VERSION 5.7 ;
  NOWIREEXTENSIONATPIN ON ;
  DIVIDERCHAR "/" ;
  BUSBITCHARS "[]" ;
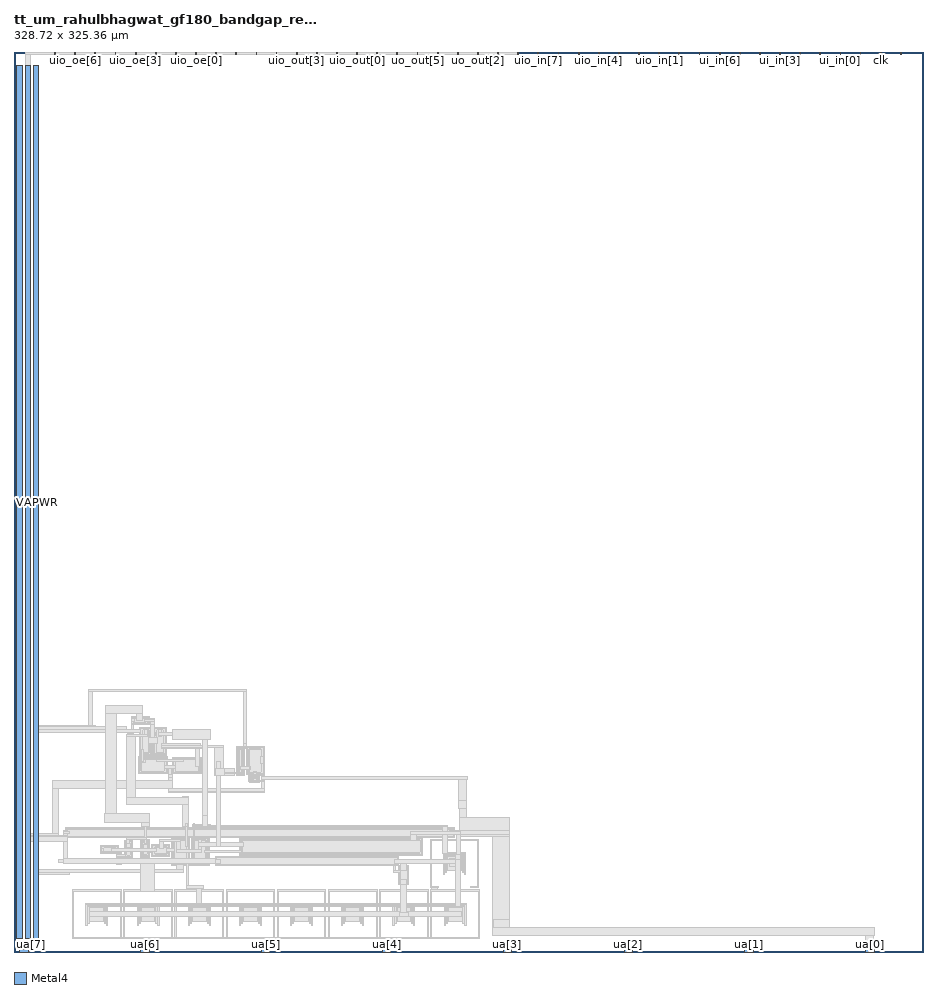
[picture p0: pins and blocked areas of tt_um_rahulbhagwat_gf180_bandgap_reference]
MACRO tt_um_rahulbhagwat_gf180_bandgap_reference
  CLASS BLOCK ;
  FOREIGN tt_um_rahulbhagwat_gf180_bandgap_reference ;
  ORIGIN 0.000 0.000 ;
  SIZE 328.720 BY 325.360 ;
  PIN clk
    DIRECTION INPUT ;
    USE SIGNAL ;
    PORT
      LAYER Metal4 ;
        RECT 313.170 324.360 313.470 325.360 ;
    END
  END clk
  PIN ena
    DIRECTION INPUT ;
    USE SIGNAL ;
    PORT
      LAYER Metal4 ;
        RECT 320.450 324.360 320.750 325.360 ;
    END
  END ena
  PIN rst_n
    DIRECTION INPUT ;
    USE SIGNAL ;
    PORT
      LAYER Metal4 ;
        RECT 305.890 324.360 306.190 325.360 ;
    END
  END rst_n
  PIN ua[0]
    DIRECTION INOUT ;
    USE SIGNAL ;
    ANTENNAGATEAREA 416.160004 ;
    ANTENNADIFFAREA 119.787193 ;
    PORT
      LAYER Metal4 ;
        RECT 307.900 0.000 310.900 1.000 ;
    END
  END ua[0]
  PIN ua[1]
    DIRECTION INOUT ;
    USE SIGNAL ;
    PORT
      LAYER Metal4 ;
        RECT 264.220 0.000 267.220 1.000 ;
    END
  END ua[1]
  PIN ua[2]
    DIRECTION INOUT ;
    USE SIGNAL ;
    PORT
      LAYER Metal4 ;
        RECT 220.540 0.000 223.540 1.000 ;
    END
  END ua[2]
  PIN ua[3]
    DIRECTION INOUT ;
    USE SIGNAL ;
    PORT
      LAYER Metal4 ;
        RECT 176.860 0.000 179.860 1.000 ;
    END
  END ua[3]
  PIN ua[4]
    DIRECTION INOUT ;
    USE SIGNAL ;
    PORT
      LAYER Metal4 ;
        RECT 133.180 0.000 136.180 1.000 ;
    END
  END ua[4]
  PIN ua[5]
    DIRECTION INOUT ;
    USE SIGNAL ;
    PORT
      LAYER Metal4 ;
        RECT 89.500 0.000 92.500 1.000 ;
    END
  END ua[5]
  PIN ua[6]
    DIRECTION INOUT ;
    USE SIGNAL ;
    PORT
      LAYER Metal4 ;
        RECT 45.820 0.000 48.820 1.000 ;
    END
  END ua[6]
  PIN ua[7]
    DIRECTION INOUT ;
    USE SIGNAL ;
    PORT
      LAYER Metal4 ;
        RECT 2.140 0.000 5.140 1.000 ;
    END
  END ua[7]
  PIN ui_in[0]
    DIRECTION INPUT ;
    USE SIGNAL ;
    PORT
      LAYER Metal4 ;
        RECT 298.610 324.360 298.910 325.360 ;
    END
  END ui_in[0]
  PIN ui_in[1]
    DIRECTION INPUT ;
    USE SIGNAL ;
    PORT
      LAYER Metal4 ;
        RECT 291.330 324.360 291.630 325.360 ;
    END
  END ui_in[1]
  PIN ui_in[2]
    DIRECTION INPUT ;
    USE SIGNAL ;
    PORT
      LAYER Metal4 ;
        RECT 284.050 324.360 284.350 325.360 ;
    END
  END ui_in[2]
  PIN ui_in[3]
    DIRECTION INPUT ;
    USE SIGNAL ;
    PORT
      LAYER Metal4 ;
        RECT 276.770 324.360 277.070 325.360 ;
    END
  END ui_in[3]
  PIN ui_in[4]
    DIRECTION INPUT ;
    USE SIGNAL ;
    PORT
      LAYER Metal4 ;
        RECT 269.490 324.360 269.790 325.360 ;
    END
  END ui_in[4]
  PIN ui_in[5]
    DIRECTION INPUT ;
    USE SIGNAL ;
    PORT
      LAYER Metal4 ;
        RECT 262.210 324.360 262.510 325.360 ;
    END
  END ui_in[5]
  PIN ui_in[6]
    DIRECTION INPUT ;
    USE SIGNAL ;
    PORT
      LAYER Metal4 ;
        RECT 254.930 324.360 255.230 325.360 ;
    END
  END ui_in[6]
  PIN ui_in[7]
    DIRECTION INPUT ;
    USE SIGNAL ;
    PORT
      LAYER Metal4 ;
        RECT 247.650 324.360 247.950 325.360 ;
    END
  END ui_in[7]
  PIN uio_in[0]
    DIRECTION INPUT ;
    USE SIGNAL ;
    PORT
      LAYER Metal4 ;
        RECT 240.370 324.360 240.670 325.360 ;
    END
  END uio_in[0]
  PIN uio_in[1]
    DIRECTION INPUT ;
    USE SIGNAL ;
    PORT
      LAYER Metal4 ;
        RECT 233.090 324.360 233.390 325.360 ;
    END
  END uio_in[1]
  PIN uio_in[2]
    DIRECTION INPUT ;
    USE SIGNAL ;
    PORT
      LAYER Metal4 ;
        RECT 225.810 324.360 226.110 325.360 ;
    END
  END uio_in[2]
  PIN uio_in[3]
    DIRECTION INPUT ;
    USE SIGNAL ;
    PORT
      LAYER Metal4 ;
        RECT 218.530 324.360 218.830 325.360 ;
    END
  END uio_in[3]
  PIN uio_in[4]
    DIRECTION INPUT ;
    USE SIGNAL ;
    PORT
      LAYER Metal4 ;
        RECT 211.250 324.360 211.550 325.360 ;
    END
  END uio_in[4]
  PIN uio_in[5]
    DIRECTION INPUT ;
    USE SIGNAL ;
    PORT
      LAYER Metal4 ;
        RECT 203.970 324.360 204.270 325.360 ;
    END
  END uio_in[5]
  PIN uio_in[6]
    DIRECTION INPUT ;
    USE SIGNAL ;
    PORT
      LAYER Metal4 ;
        RECT 196.690 324.360 196.990 325.360 ;
    END
  END uio_in[6]
  PIN uio_in[7]
    DIRECTION INPUT ;
    USE SIGNAL ;
    PORT
      LAYER Metal4 ;
        RECT 189.410 324.360 189.710 325.360 ;
    END
  END uio_in[7]
  PIN uio_oe[0]
    DIRECTION OUTPUT ;
    USE SIGNAL ;
    ANTENNADIFFAREA 455.790802 ;
    PORT
      LAYER Metal4 ;
        RECT 65.650 324.360 65.950 325.360 ;
    END
  END uio_oe[0]
  PIN uio_oe[1]
    DIRECTION OUTPUT ;
    USE SIGNAL ;
    ANTENNADIFFAREA 455.790802 ;
    PORT
      LAYER Metal4 ;
        RECT 58.370 324.360 58.670 325.360 ;
    END
  END uio_oe[1]
  PIN uio_oe[2]
    DIRECTION OUTPUT ;
    USE SIGNAL ;
    ANTENNADIFFAREA 455.790802 ;
    PORT
      LAYER Metal4 ;
        RECT 51.090 324.360 51.390 325.360 ;
    END
  END uio_oe[2]
  PIN uio_oe[3]
    DIRECTION OUTPUT ;
    USE SIGNAL ;
    ANTENNADIFFAREA 455.790802 ;
    PORT
      LAYER Metal4 ;
        RECT 43.810 324.360 44.110 325.360 ;
    END
  END uio_oe[3]
  PIN uio_oe[4]
    DIRECTION OUTPUT ;
    USE SIGNAL ;
    ANTENNADIFFAREA 455.790802 ;
    PORT
      LAYER Metal4 ;
        RECT 36.530 324.360 36.830 325.360 ;
    END
  END uio_oe[4]
  PIN uio_oe[5]
    DIRECTION OUTPUT ;
    USE SIGNAL ;
    ANTENNADIFFAREA 455.790802 ;
    PORT
      LAYER Metal4 ;
        RECT 29.250 324.360 29.550 325.360 ;
    END
  END uio_oe[5]
  PIN uio_oe[6]
    DIRECTION OUTPUT ;
    USE SIGNAL ;
    ANTENNADIFFAREA 455.790802 ;
    PORT
      LAYER Metal4 ;
        RECT 21.970 324.360 22.270 325.360 ;
    END
  END uio_oe[6]
  PIN uio_oe[7]
    DIRECTION OUTPUT ;
    USE SIGNAL ;
    ANTENNADIFFAREA 455.790802 ;
    PORT
      LAYER Metal4 ;
        RECT 14.690 324.360 14.990 325.360 ;
    END
  END uio_oe[7]
  PIN uio_out[0]
    DIRECTION OUTPUT ;
    USE SIGNAL ;
    ANTENNADIFFAREA 455.790802 ;
    PORT
      LAYER Metal4 ;
        RECT 123.890 324.360 124.190 325.360 ;
    END
  END uio_out[0]
  PIN uio_out[1]
    DIRECTION OUTPUT ;
    USE SIGNAL ;
    ANTENNADIFFAREA 455.790802 ;
    PORT
      LAYER Metal4 ;
        RECT 116.610 324.360 116.910 325.360 ;
    END
  END uio_out[1]
  PIN uio_out[2]
    DIRECTION OUTPUT ;
    USE SIGNAL ;
    ANTENNADIFFAREA 455.790802 ;
    PORT
      LAYER Metal4 ;
        RECT 109.330 324.360 109.630 325.360 ;
    END
  END uio_out[2]
  PIN uio_out[3]
    DIRECTION OUTPUT ;
    USE SIGNAL ;
    ANTENNADIFFAREA 455.790802 ;
    PORT
      LAYER Metal4 ;
        RECT 102.050 324.360 102.350 325.360 ;
    END
  END uio_out[3]
  PIN uio_out[4]
    DIRECTION OUTPUT ;
    USE SIGNAL ;
    ANTENNADIFFAREA 455.790802 ;
    PORT
      LAYER Metal4 ;
        RECT 94.770 324.360 95.070 325.360 ;
    END
  END uio_out[4]
  PIN uio_out[5]
    DIRECTION OUTPUT ;
    USE SIGNAL ;
    ANTENNADIFFAREA 455.790802 ;
    PORT
      LAYER Metal4 ;
        RECT 87.490 324.360 87.790 325.360 ;
    END
  END uio_out[5]
  PIN uio_out[6]
    DIRECTION OUTPUT ;
    USE SIGNAL ;
    ANTENNADIFFAREA 455.790802 ;
    PORT
      LAYER Metal4 ;
        RECT 80.210 324.360 80.510 325.360 ;
    END
  END uio_out[6]
  PIN uio_out[7]
    DIRECTION OUTPUT ;
    USE SIGNAL ;
    ANTENNADIFFAREA 455.790802 ;
    PORT
      LAYER Metal4 ;
        RECT 72.930 324.360 73.230 325.360 ;
    END
  END uio_out[7]
  PIN uo_out[0]
    DIRECTION OUTPUT ;
    USE SIGNAL ;
    ANTENNADIFFAREA 455.790802 ;
    PORT
      LAYER Metal4 ;
        RECT 182.130 324.360 182.430 325.360 ;
    END
  END uo_out[0]
  PIN uo_out[1]
    DIRECTION OUTPUT ;
    USE SIGNAL ;
    ANTENNADIFFAREA 455.790802 ;
    PORT
      LAYER Metal4 ;
        RECT 174.850 324.360 175.150 325.360 ;
    END
  END uo_out[1]
  PIN uo_out[2]
    DIRECTION OUTPUT ;
    USE SIGNAL ;
    ANTENNADIFFAREA 455.790802 ;
    PORT
      LAYER Metal4 ;
        RECT 167.570 324.360 167.870 325.360 ;
    END
  END uo_out[2]
  PIN uo_out[3]
    DIRECTION OUTPUT ;
    USE SIGNAL ;
    ANTENNADIFFAREA 455.790802 ;
    PORT
      LAYER Metal4 ;
        RECT 160.290 324.360 160.590 325.360 ;
    END
  END uo_out[3]
  PIN uo_out[4]
    DIRECTION OUTPUT ;
    USE SIGNAL ;
    ANTENNADIFFAREA 455.790802 ;
    PORT
      LAYER Metal4 ;
        RECT 153.010 324.360 153.310 325.360 ;
    END
  END uo_out[4]
  PIN uo_out[5]
    DIRECTION OUTPUT ;
    USE SIGNAL ;
    ANTENNADIFFAREA 455.790802 ;
    PORT
      LAYER Metal4 ;
        RECT 145.730 324.360 146.030 325.360 ;
    END
  END uo_out[5]
  PIN uo_out[6]
    DIRECTION OUTPUT ;
    USE SIGNAL ;
    ANTENNADIFFAREA 455.790802 ;
    PORT
      LAYER Metal4 ;
        RECT 138.450 324.360 138.750 325.360 ;
    END
  END uo_out[6]
  PIN uo_out[7]
    DIRECTION OUTPUT ;
    USE SIGNAL ;
    ANTENNADIFFAREA 455.790802 ;
    PORT
      LAYER Metal4 ;
        RECT 131.170 324.360 131.470 325.360 ;
    END
  END uo_out[7]
  PIN VDPWR
    DIRECTION INOUT ;
    USE POWER ;
    PORT
      LAYER Metal4 ;
        RECT 1.000 5.000 3.000 320.360 ;
    END
  END VDPWR
  PIN VGND
    DIRECTION INOUT ;
    USE GROUND ;
    PORT
      LAYER Metal4 ;
        RECT 4.000 5.000 6.000 320.360 ;
    END
  END VGND
  PIN VAPWR
    DIRECTION INOUT ;
    USE POWER ;
    PORT
      LAYER Metal4 ;
        RECT 7.000 5.000 9.000 320.360 ;
    END
  END VAPWR
  OBS
      LAYER Nwell ;
        RECT 42.350 82.205 48.850 85.305 ;
        RECT 45.400 71.155 49.900 81.255 ;
        RECT 50.550 71.205 55.050 81.305 ;
      LAYER Pwell ;
        RECT 44.950 64.405 55.450 70.505 ;
        RECT 57.410 64.370 67.910 70.470 ;
      LAYER Nwell ;
        RECT 80.600 63.850 83.200 74.350 ;
        RECT 83.950 64.150 90.450 74.250 ;
      LAYER Pwell ;
        RECT 85.300 61.250 88.840 63.650 ;
        RECT 18.750 41.500 159.330 44.860 ;
        RECT 31.300 35.450 37.800 38.550 ;
        RECT 39.800 33.950 42.900 40.450 ;
      LAYER Nwell ;
        RECT 45.900 34.300 49.000 40.800 ;
        RECT 49.750 34.650 56.250 38.750 ;
        RECT 56.900 31.150 63.400 41.250 ;
        RECT 64.000 31.200 70.500 41.300 ;
        RECT 81.650 34.900 147.750 41.400 ;
      LAYER Pwell ;
        RECT 72.900 31.100 139.130 34.460 ;
        RECT 139.150 24.550 142.690 31.130 ;
      LAYER Metal1 ;
        RECT 26.950 94.000 84.150 95.000 ;
        RECT 26.950 82.000 28.300 94.000 ;
        RECT 44.445 87.280 45.445 88.280 ;
        RECT 42.535 84.890 48.665 85.120 ;
        RECT 42.535 84.305 42.765 84.890 ;
        RECT 43.610 84.420 47.590 84.650 ;
        RECT 42.535 84.245 43.300 84.305 ;
        RECT 42.535 83.265 43.455 84.245 ;
        RECT 44.440 83.715 46.420 84.420 ;
        RECT 47.745 84.140 47.975 84.245 ;
        RECT 47.115 83.350 47.975 84.140 ;
        RECT 47.745 83.265 47.975 83.350 ;
        RECT 42.535 83.255 43.300 83.265 ;
        RECT 42.535 82.620 43.050 83.255 ;
        RECT 43.610 82.860 47.590 83.090 ;
        RECT 48.435 82.620 48.665 84.890 ;
        RECT 42.535 82.390 48.665 82.620 ;
        RECT 6.950 81.500 29.350 82.000 ;
        RECT 6.950 80.405 40.800 81.500 ;
        RECT 42.550 80.405 43.050 82.390 ;
        RECT 45.585 80.840 49.715 81.070 ;
        RECT 45.585 80.405 45.815 80.840 ;
        RECT 6.950 79.405 45.850 80.405 ;
        RECT 46.660 80.370 48.640 80.600 ;
        RECT 6.950 79.350 40.800 79.405 ;
        RECT 26.950 79.300 40.800 79.350 ;
        RECT 26.950 79.250 28.300 79.300 ;
        RECT 41.140 76.595 42.740 79.095 ;
        RECT 45.585 71.570 45.815 79.405 ;
        RECT 46.275 73.265 46.505 80.195 ;
        RECT 47.215 77.895 48.180 80.370 ;
        RECT 48.795 77.405 49.025 80.195 ;
        RECT 49.485 79.405 49.715 80.840 ;
        RECT 50.735 80.890 54.865 81.120 ;
        RECT 50.735 79.405 50.965 80.890 ;
        RECT 51.810 80.420 53.790 80.650 ;
        RECT 49.450 78.405 51.000 79.405 ;
        RECT 48.450 75.405 49.050 77.405 ;
        RECT 46.045 72.410 46.750 73.265 ;
        RECT 46.275 72.215 46.505 72.410 ;
        RECT 48.795 72.215 49.025 75.405 ;
        RECT 46.660 71.810 48.640 72.040 ;
        RECT 49.485 71.570 49.715 78.405 ;
        RECT 45.585 71.340 49.715 71.570 ;
        RECT 50.735 71.620 50.965 78.405 ;
        RECT 51.425 77.405 51.655 80.245 ;
        RECT 52.285 77.975 53.410 80.420 ;
        RECT 51.400 75.405 51.850 77.405 ;
        RECT 51.425 72.265 51.655 75.405 ;
        RECT 53.945 75.400 54.175 80.245 ;
        RECT 53.435 73.760 54.180 75.400 ;
        RECT 53.945 72.265 54.175 73.760 ;
        RECT 51.810 71.860 53.790 72.090 ;
        RECT 54.635 71.620 54.865 80.890 ;
        RECT 57.715 77.440 60.315 79.940 ;
        RECT 82.900 75.250 84.150 94.000 ;
        RECT 68.485 73.725 69.485 74.725 ;
        RECT 82.900 74.165 83.900 75.250 ;
        RECT 80.785 74.150 83.900 74.165 ;
        RECT 80.785 74.065 84.350 74.150 ;
        RECT 80.785 73.935 90.265 74.065 ;
        RECT 50.735 71.390 54.865 71.620 ;
        RECT 45.135 70.090 55.265 70.320 ;
        RECT 45.135 64.820 45.365 70.090 ;
        RECT 51.450 69.850 53.410 69.855 ;
        RECT 46.210 69.845 54.190 69.850 ;
        RECT 45.800 69.620 54.190 69.845 ;
        RECT 45.800 68.400 47.450 69.620 ;
        RECT 51.450 68.905 53.410 69.620 ;
        RECT 45.825 65.465 46.055 68.400 ;
        RECT 54.345 67.390 54.575 69.445 ;
        RECT 55.035 67.390 55.265 70.090 ;
        RECT 57.595 70.055 67.725 70.285 ;
        RECT 57.595 67.390 57.825 70.055 ;
        RECT 58.670 69.585 66.650 69.815 ;
        RECT 58.285 67.390 58.515 69.410 ;
        RECT 59.455 68.935 61.445 69.585 ;
        RECT 66.805 68.685 67.035 69.410 ;
        RECT 54.325 66.395 58.525 67.390 ;
        RECT 65.920 67.275 67.070 68.685 ;
        RECT 54.345 65.465 54.575 66.395 ;
        RECT 46.210 65.060 54.190 65.290 ;
        RECT 55.035 64.820 55.265 66.395 ;
        RECT 45.135 64.590 55.265 64.820 ;
        RECT 55.775 64.100 57.015 66.395 ;
        RECT 57.595 64.785 57.825 66.395 ;
        RECT 58.285 65.430 58.515 66.395 ;
        RECT 66.805 65.430 67.035 67.275 ;
        RECT 58.670 65.025 66.650 65.255 ;
        RECT 67.495 64.785 67.725 70.055 ;
        RECT 57.595 64.555 67.725 64.785 ;
        RECT 78.000 65.000 79.000 65.200 ;
        RECT 78.000 64.500 79.700 65.000 ;
        RECT 78.000 64.200 79.000 64.500 ;
        RECT 80.785 64.265 81.015 73.935 ;
        RECT 81.400 73.835 90.265 73.935 ;
        RECT 81.400 73.650 84.365 73.835 ;
        RECT 81.400 73.350 82.450 73.650 ;
        RECT 81.660 73.245 82.140 73.350 ;
        RECT 81.255 65.110 81.485 73.090 ;
        RECT 82.315 66.900 82.545 73.090 ;
        RECT 82.000 66.000 82.550 66.900 ;
        RECT 82.315 65.110 82.545 66.000 ;
        RECT 81.660 64.850 82.140 64.955 ;
        RECT 81.350 64.500 82.350 64.850 ;
        RECT 82.785 64.265 83.015 73.650 ;
        RECT 84.135 64.565 84.365 73.650 ;
        RECT 85.210 73.365 89.190 73.595 ;
        RECT 84.825 67.050 85.055 73.190 ;
        RECT 89.345 70.650 89.575 73.190 ;
        RECT 90.035 70.650 90.265 73.835 ;
        RECT 89.250 68.150 90.265 70.650 ;
        RECT 84.750 65.850 85.600 67.050 ;
        RECT 84.825 65.210 85.055 65.850 ;
        RECT 89.345 65.210 89.575 68.150 ;
        RECT 86.550 65.035 87.550 65.200 ;
        RECT 85.210 64.805 89.190 65.035 ;
        RECT 86.550 64.800 87.550 64.805 ;
        RECT 90.035 64.565 90.265 68.150 ;
        RECT 84.135 64.335 90.265 64.565 ;
        RECT 55.750 63.250 57.200 64.100 ;
        RECT 80.785 64.035 83.015 64.265 ;
        RECT 14.000 61.900 30.000 62.050 ;
        RECT 13.950 61.850 30.000 61.900 ;
        RECT 55.700 61.850 57.400 63.250 ;
        RECT 13.950 59.000 57.400 61.850 ;
        RECT 85.485 63.235 88.655 63.465 ;
        RECT 85.485 61.665 85.715 63.235 ;
        RECT 85.950 62.565 86.350 62.950 ;
        RECT 86.580 62.765 87.560 62.995 ;
        RECT 86.855 62.670 87.405 62.765 ;
        RECT 88.425 62.700 88.655 63.235 ;
        RECT 87.900 62.565 88.700 62.700 ;
        RECT 85.950 62.335 86.460 62.565 ;
        RECT 87.680 62.335 88.700 62.565 ;
        RECT 89.395 62.390 90.395 63.390 ;
        RECT 85.950 61.950 86.350 62.335 ;
        RECT 87.900 62.150 88.700 62.335 ;
        RECT 86.580 61.905 87.560 62.135 ;
        RECT 87.900 62.100 90.450 62.150 ;
        RECT 88.350 61.665 90.450 62.100 ;
        RECT 85.485 61.550 90.450 61.665 ;
        RECT 85.485 61.435 88.655 61.550 ;
        RECT 13.950 43.000 15.950 59.000 ;
        RECT 28.000 58.950 57.400 59.000 ;
        RECT 89.400 58.950 90.450 61.550 ;
        RECT 55.700 58.000 90.700 58.950 ;
        RECT 55.900 57.800 90.700 58.000 ;
        RECT 73.500 47.250 74.500 48.250 ;
        RECT 46.950 45.550 47.950 46.550 ;
        RECT 61.900 45.350 62.900 46.350 ;
        RECT 64.500 45.100 65.500 46.100 ;
        RECT 18.935 44.445 159.145 44.675 ;
        RECT 18.935 43.750 19.165 44.445 ;
        RECT 17.900 43.650 19.500 43.750 ;
        RECT 19.995 43.650 20.225 43.670 ;
        RECT 4.000 41.950 16.000 43.000 ;
        RECT 17.900 42.700 20.225 43.650 ;
        RECT 157.600 42.700 158.150 43.700 ;
        RECT 17.900 41.950 19.500 42.700 ;
        RECT 19.995 42.690 20.225 42.700 ;
        RECT 157.855 42.690 158.085 42.700 ;
        RECT 4.000 41.915 19.500 41.950 ;
        RECT 158.915 41.915 159.145 44.445 ;
        RECT 161.900 42.900 163.650 43.850 ;
        RECT 4.000 41.685 159.145 41.915 ;
        RECT 4.000 40.000 19.500 41.685 ;
        RECT 57.085 40.835 63.215 41.065 ;
        RECT 46.085 40.385 48.815 40.615 ;
        RECT 13.950 39.950 15.950 40.000 ;
        RECT 17.900 33.500 19.500 40.000 ;
        RECT 39.985 40.035 42.715 40.265 ;
        RECT 31.485 38.135 37.615 38.365 ;
        RECT 31.485 37.500 31.715 38.135 ;
        RECT 35.250 37.895 36.100 37.900 ;
        RECT 32.560 37.665 36.540 37.895 ;
        RECT 31.485 37.490 32.350 37.500 ;
        RECT 31.485 36.510 32.405 37.490 ;
        RECT 31.485 36.500 32.350 36.510 ;
        RECT 31.485 35.865 31.715 36.500 ;
        RECT 35.250 36.335 36.100 37.665 ;
        RECT 36.695 37.350 36.925 37.490 ;
        RECT 36.550 36.750 36.950 37.350 ;
        RECT 36.695 36.510 36.925 36.750 ;
        RECT 32.560 36.105 36.540 36.335 ;
        RECT 35.250 36.100 36.100 36.105 ;
        RECT 37.385 35.865 37.615 38.135 ;
        RECT 31.485 35.850 37.615 35.865 ;
        RECT 31.485 35.635 38.900 35.850 ;
        RECT 36.950 35.350 38.900 35.635 ;
        RECT 39.985 35.350 40.215 40.035 ;
        RECT 40.950 39.575 41.800 39.800 ;
        RECT 40.860 39.345 41.840 39.575 ;
        RECT 36.950 35.300 40.215 35.350 ;
        RECT 16.100 32.500 19.500 33.500 ;
        RECT 17.900 31.850 19.500 32.500 ;
        RECT 37.000 34.365 40.215 35.300 ;
        RECT 40.455 37.800 40.685 39.190 ;
        RECT 42.015 37.800 42.245 39.190 ;
        RECT 40.455 36.350 42.245 37.800 ;
        RECT 40.455 35.210 40.685 36.350 ;
        RECT 42.015 35.210 42.245 36.350 ;
        RECT 40.860 34.825 41.840 35.055 ;
        RECT 40.900 34.365 41.800 34.825 ;
        RECT 42.485 34.365 42.715 40.035 ;
        RECT 46.085 34.715 46.315 40.385 ;
        RECT 46.960 39.800 47.940 39.925 ;
        RECT 46.750 39.540 48.200 39.800 ;
        RECT 46.555 38.950 48.345 39.540 ;
        RECT 46.555 35.560 46.785 38.950 ;
        RECT 48.115 35.560 48.345 38.950 ;
        RECT 48.585 37.400 48.815 40.385 ;
        RECT 49.935 38.335 56.065 38.565 ;
        RECT 49.935 37.400 50.165 38.335 ;
        RECT 51.010 37.865 54.990 38.095 ;
        RECT 48.585 35.850 50.200 37.400 ;
        RECT 50.625 37.300 50.855 37.690 ;
        RECT 52.900 37.450 53.900 37.865 ;
        RECT 55.145 37.300 55.375 37.690 ;
        RECT 55.835 37.300 56.065 38.335 ;
        RECT 57.085 37.300 57.315 40.835 ;
        RECT 59.050 40.595 60.150 40.600 ;
        RECT 58.160 40.365 62.140 40.595 ;
        RECT 57.775 37.300 58.005 40.190 ;
        RECT 59.050 40.100 60.150 40.365 ;
        RECT 62.295 39.300 62.525 40.190 ;
        RECT 62.150 38.300 62.600 39.300 ;
        RECT 50.625 36.300 51.400 37.300 ;
        RECT 55.145 36.300 58.005 37.300 ;
        RECT 46.960 35.175 47.940 35.405 ;
        RECT 47.050 34.715 47.850 35.175 ;
        RECT 48.585 34.715 48.815 35.850 ;
        RECT 49.935 35.065 50.165 35.850 ;
        RECT 50.625 35.710 50.855 36.300 ;
        RECT 55.145 35.710 55.375 36.300 ;
        RECT 51.010 35.305 54.990 35.535 ;
        RECT 55.835 35.065 56.065 36.300 ;
        RECT 49.935 34.835 56.065 35.065 ;
        RECT 46.085 34.485 48.815 34.715 ;
        RECT 37.000 34.200 42.715 34.365 ;
        RECT 37.000 31.850 38.900 34.200 ;
        RECT 39.985 34.135 42.715 34.200 ;
        RECT 57.085 31.565 57.315 36.300 ;
        RECT 57.775 32.210 58.005 36.300 ;
        RECT 62.295 33.650 62.525 38.300 ;
        RECT 62.295 32.350 62.750 33.650 ;
        RECT 62.295 32.210 62.525 32.350 ;
        RECT 62.985 32.150 63.215 40.835 ;
        RECT 64.185 40.885 70.315 41.115 ;
        RECT 64.185 32.150 64.415 40.885 ;
        RECT 65.260 40.415 69.240 40.645 ;
        RECT 66.850 40.250 67.950 40.415 ;
        RECT 64.875 39.300 65.105 40.240 ;
        RECT 64.800 38.300 65.250 39.300 ;
        RECT 64.875 32.260 65.105 38.300 ;
        RECT 69.395 36.750 69.625 40.240 ;
        RECT 70.085 36.750 70.315 40.885 ;
        RECT 81.835 40.985 147.565 41.215 ;
        RECT 81.835 36.750 82.065 40.985 ;
        RECT 143.400 40.525 145.350 40.650 ;
        RECT 82.710 40.295 146.690 40.525 ;
        RECT 143.400 40.250 145.350 40.295 ;
        RECT 82.305 39.300 82.535 40.140 ;
        RECT 82.300 38.300 82.700 39.300 ;
        RECT 68.900 35.800 82.065 36.750 ;
        RECT 82.305 36.160 82.535 38.300 ;
        RECT 146.865 36.160 147.095 40.140 ;
        RECT 69.395 32.260 69.625 35.800 ;
        RECT 58.160 31.805 62.140 32.035 ;
        RECT 62.985 31.615 64.415 32.150 ;
        RECT 65.260 31.855 69.240 32.085 ;
        RECT 70.085 31.615 70.315 35.800 ;
        RECT 81.835 35.315 82.065 35.800 ;
        RECT 82.710 35.775 146.690 36.005 ;
        RECT 143.600 35.315 145.250 35.775 ;
        RECT 147.335 35.315 147.565 40.985 ;
        RECT 81.835 35.085 147.565 35.315 ;
        RECT 150.400 40.420 168.040 40.840 ;
        RECT 73.085 34.045 138.945 34.275 ;
        RECT 73.085 33.450 73.315 34.045 ;
        RECT 73.050 32.150 74.450 33.450 ;
        RECT 137.400 32.300 137.950 33.300 ;
        RECT 137.655 32.290 137.885 32.300 ;
        RECT 62.985 31.565 70.315 31.615 ;
        RECT 57.085 31.400 70.315 31.565 ;
        RECT 57.085 31.335 63.215 31.400 ;
        RECT 64.185 31.385 70.315 31.400 ;
        RECT 73.085 31.515 73.315 32.150 ;
        RECT 138.715 31.515 138.945 34.045 ;
        RECT 58.850 30.300 61.400 31.335 ;
        RECT 73.085 31.285 138.945 31.515 ;
        RECT 17.900 28.750 18.900 29.750 ;
        RECT 137.350 29.300 137.900 31.285 ;
        RECT 139.335 30.715 142.505 30.945 ;
        RECT 139.335 29.300 139.565 30.715 ;
        RECT 140.350 29.885 141.500 29.900 ;
        RECT 140.340 29.655 141.500 29.885 ;
        RECT 140.350 29.500 141.500 29.655 ;
        RECT 137.350 28.800 139.600 29.300 ;
        RECT 139.335 24.965 139.565 28.800 ;
        RECT 140.350 26.025 141.500 26.200 ;
        RECT 140.340 25.795 141.500 26.025 ;
        RECT 142.275 24.965 142.505 30.715 ;
        RECT 139.335 24.735 142.505 24.965 ;
        RECT 150.400 23.620 150.820 40.420 ;
        RECT 155.250 36.000 156.500 36.550 ;
        RECT 155.240 35.580 163.200 36.000 ;
        RECT 155.240 28.040 155.660 35.580 ;
        RECT 155.980 34.840 162.460 35.260 ;
        RECT 155.980 28.780 156.400 34.840 ;
        RECT 156.720 29.520 161.720 34.520 ;
        RECT 162.040 28.780 162.460 34.840 ;
        RECT 162.780 28.040 163.200 35.580 ;
        RECT 167.620 23.620 168.040 40.420 ;
        RECT 150.400 23.200 153.320 23.620 ;
        RECT 165.120 23.600 168.040 23.620 ;
        RECT 165.120 23.200 168.050 23.600 ;
        RECT 150.900 22.440 152.950 23.200 ;
        RECT 21.150 22.020 38.790 22.440 ;
        RECT 21.150 5.220 21.570 22.020 ;
        RECT 25.990 17.180 33.950 17.600 ;
        RECT 25.990 9.640 26.410 17.180 ;
        RECT 26.730 16.440 33.210 16.860 ;
        RECT 26.730 10.380 27.150 16.440 ;
        RECT 27.470 11.120 32.470 16.120 ;
        RECT 32.790 10.380 33.210 16.440 ;
        RECT 33.530 9.640 33.950 17.180 ;
        RECT 38.370 5.220 38.790 22.020 ;
        RECT 21.150 5.200 24.070 5.220 ;
        RECT 35.870 5.200 38.790 5.220 ;
        RECT 39.650 22.020 57.290 22.440 ;
        RECT 39.650 5.220 40.070 22.020 ;
        RECT 44.490 17.180 52.450 17.600 ;
        RECT 44.490 9.640 44.910 17.180 ;
        RECT 45.230 16.440 51.710 16.860 ;
        RECT 45.230 10.380 45.650 16.440 ;
        RECT 45.970 11.120 50.970 16.120 ;
        RECT 51.290 10.380 51.710 16.440 ;
        RECT 52.030 9.640 52.450 17.180 ;
        RECT 56.870 5.220 57.290 22.020 ;
        RECT 39.650 5.200 42.570 5.220 ;
        RECT 54.370 5.200 57.290 5.220 ;
        RECT 58.150 22.020 75.790 22.440 ;
        RECT 58.150 5.220 58.570 22.020 ;
        RECT 62.990 17.180 70.950 17.600 ;
        RECT 62.990 9.640 63.410 17.180 ;
        RECT 63.730 16.440 70.210 16.860 ;
        RECT 63.730 10.380 64.150 16.440 ;
        RECT 64.470 11.120 69.470 16.120 ;
        RECT 69.790 10.380 70.210 16.440 ;
        RECT 70.530 9.640 70.950 17.180 ;
        RECT 75.370 5.220 75.790 22.020 ;
        RECT 58.150 5.200 61.070 5.220 ;
        RECT 72.870 5.200 75.790 5.220 ;
        RECT 76.650 22.020 94.290 22.440 ;
        RECT 76.650 5.220 77.070 22.020 ;
        RECT 81.490 17.180 89.450 17.600 ;
        RECT 81.490 9.640 81.910 17.180 ;
        RECT 82.230 16.440 88.710 16.860 ;
        RECT 82.230 10.380 82.650 16.440 ;
        RECT 82.970 11.120 87.970 16.120 ;
        RECT 88.290 10.380 88.710 16.440 ;
        RECT 89.030 9.640 89.450 17.180 ;
        RECT 93.870 5.220 94.290 22.020 ;
        RECT 76.650 5.200 79.570 5.220 ;
        RECT 91.370 5.200 94.290 5.220 ;
        RECT 95.150 22.020 112.790 22.440 ;
        RECT 95.150 5.220 95.570 22.020 ;
        RECT 99.990 17.180 107.950 17.600 ;
        RECT 99.990 9.640 100.410 17.180 ;
        RECT 100.730 16.440 107.210 16.860 ;
        RECT 100.730 10.380 101.150 16.440 ;
        RECT 101.470 11.120 106.470 16.120 ;
        RECT 106.790 10.380 107.210 16.440 ;
        RECT 107.530 9.640 107.950 17.180 ;
        RECT 112.370 5.220 112.790 22.020 ;
        RECT 95.150 5.200 98.070 5.220 ;
        RECT 109.870 5.200 112.790 5.220 ;
        RECT 113.650 22.020 131.290 22.440 ;
        RECT 113.650 5.220 114.070 22.020 ;
        RECT 118.490 17.180 126.450 17.600 ;
        RECT 118.490 9.640 118.910 17.180 ;
        RECT 119.230 16.440 125.710 16.860 ;
        RECT 119.230 10.380 119.650 16.440 ;
        RECT 119.970 11.120 124.970 16.120 ;
        RECT 125.290 10.380 125.710 16.440 ;
        RECT 126.030 9.640 126.450 17.180 ;
        RECT 130.870 5.220 131.290 22.020 ;
        RECT 113.650 5.200 116.570 5.220 ;
        RECT 128.370 5.200 131.290 5.220 ;
        RECT 132.150 22.020 149.790 22.440 ;
        RECT 132.150 5.220 132.570 22.020 ;
        RECT 136.990 17.180 144.950 17.600 ;
        RECT 136.990 9.640 137.410 17.180 ;
        RECT 137.730 16.440 144.210 16.860 ;
        RECT 137.730 10.380 138.150 16.440 ;
        RECT 138.470 11.120 143.470 16.120 ;
        RECT 143.790 10.380 144.210 16.440 ;
        RECT 144.530 9.640 144.950 17.180 ;
        RECT 149.370 5.220 149.790 22.020 ;
        RECT 132.150 5.200 135.070 5.220 ;
        RECT 146.870 5.200 149.790 5.220 ;
        RECT 150.650 22.020 168.290 22.440 ;
        RECT 150.650 5.220 151.070 22.020 ;
        RECT 155.490 17.180 163.450 17.600 ;
        RECT 155.490 9.640 155.910 17.180 ;
        RECT 156.230 16.440 162.710 16.860 ;
        RECT 156.230 10.380 156.650 16.440 ;
        RECT 156.970 11.120 161.970 16.120 ;
        RECT 162.290 10.380 162.710 16.440 ;
        RECT 163.030 9.640 163.450 17.180 ;
        RECT 167.870 5.220 168.290 22.020 ;
        RECT 150.650 5.200 153.570 5.220 ;
        RECT 165.370 5.200 168.290 5.220 ;
        RECT 21.150 4.800 168.300 5.200 ;
      LAYER Metal2 ;
        RECT 32.900 86.350 46.350 89.000 ;
        RECT 7.000 79.350 9.000 82.000 ;
        RECT 32.900 50.000 36.950 86.350 ;
        RECT 44.155 83.715 46.345 86.350 ;
        RECT 49.435 84.125 50.885 84.385 ;
        RECT 47.130 83.405 50.885 84.125 ;
        RECT 47.130 83.370 50.900 83.405 ;
        RECT 49.435 82.390 50.900 83.370 ;
        RECT 41.140 79.085 42.790 79.095 ;
        RECT 40.865 78.650 43.285 79.085 ;
        RECT 40.700 77.865 48.235 78.650 ;
        RECT 40.700 56.000 44.050 77.865 ;
        RECT 49.450 77.405 50.900 82.390 ;
        RECT 57.400 79.405 61.050 80.300 ;
        RECT 52.275 78.100 61.050 79.405 ;
        RECT 48.450 75.405 51.850 77.405 ;
        RECT 57.400 77.350 61.050 78.100 ;
        RECT 53.445 74.725 67.440 75.355 ;
        RECT 53.445 74.650 69.485 74.725 ;
        RECT 72.650 74.650 75.650 74.700 ;
        RECT 53.445 73.800 75.650 74.650 ;
        RECT 53.445 73.725 69.485 73.800 ;
        RECT 53.445 73.405 67.440 73.725 ;
        RECT 46.000 68.830 46.750 73.275 ;
        RECT 51.460 68.945 61.435 69.770 ;
        RECT 65.455 67.230 67.070 73.405 ;
        RECT 72.650 66.200 75.650 73.800 ;
        RECT 72.500 65.000 79.550 66.200 ;
        RECT 82.000 65.900 85.250 67.150 ;
        RECT 72.500 64.500 82.350 65.000 ;
        RECT 72.500 63.800 79.550 64.500 ;
        RECT 84.750 62.500 85.250 65.900 ;
        RECT 86.550 64.850 87.550 65.300 ;
        RECT 86.600 64.800 87.500 64.850 ;
        RECT 86.650 64.100 87.500 64.800 ;
        RECT 86.650 64.095 88.100 64.100 ;
        RECT 86.650 64.080 90.185 64.095 ;
        RECT 86.650 63.645 90.395 64.080 ;
        RECT 86.650 63.600 87.850 63.645 ;
        RECT 86.650 62.960 87.500 63.600 ;
        RECT 89.390 63.550 90.395 63.645 ;
        RECT 89.390 63.500 96.850 63.550 ;
        RECT 86.650 62.650 87.550 62.960 ;
        RECT 84.750 61.950 86.350 62.500 ;
        RECT 89.390 62.370 164.000 63.500 ;
        RECT 89.400 62.350 164.000 62.370 ;
        RECT 94.550 62.200 164.000 62.350 ;
        RECT 84.750 61.750 85.250 61.950 ;
        RECT 61.000 56.000 63.050 56.050 ;
        RECT 40.700 53.150 63.050 56.000 ;
        RECT 32.750 46.850 49.150 50.000 ;
        RECT 46.050 45.450 49.000 46.850 ;
        RECT 46.950 45.300 47.950 45.450 ;
        RECT 61.000 45.350 63.050 53.150 ;
        RECT 160.550 54.900 163.600 62.200 ;
        RECT 160.550 51.850 163.750 54.900 ;
        RECT 160.900 48.750 163.750 51.850 ;
        RECT 73.350 47.100 74.650 48.300 ;
        RECT 64.750 46.050 71.100 46.250 ;
        RECT 64.500 45.850 71.100 46.050 ;
        RECT 64.500 45.800 156.450 45.850 ;
        RECT 4.000 40.000 6.000 42.950 ;
        RECT 47.000 41.250 47.950 45.300 ;
        RECT 64.500 45.300 156.550 45.800 ;
        RECT 64.500 45.100 65.500 45.300 ;
        RECT 40.850 40.800 47.950 41.250 ;
        RECT 40.850 39.350 41.750 40.800 ;
        RECT 47.000 39.050 47.950 40.800 ;
        RECT 52.650 40.800 54.000 40.850 ;
        RECT 52.650 40.100 60.150 40.800 ;
        RECT 35.150 36.500 51.400 37.500 ;
        RECT 52.650 37.400 54.000 40.100 ;
        RECT 40.900 36.300 51.400 36.500 ;
        RECT 58.900 37.200 60.150 40.100 ;
        RECT 66.850 39.450 67.950 40.650 ;
        RECT 143.400 40.250 145.350 40.650 ;
        RECT 62.150 38.300 62.600 39.300 ;
        RECT 64.800 38.300 65.250 39.300 ;
        RECT 66.850 38.000 82.900 39.450 ;
        RECT 66.850 37.200 67.900 38.000 ;
        RECT 58.900 36.000 67.900 37.200 ;
        RECT 58.900 35.950 60.150 36.000 ;
        RECT 155.000 35.650 156.550 45.300 ;
        RECT 160.900 43.850 179.000 48.750 ;
        RECT 157.500 42.400 179.000 43.850 ;
        RECT 159.900 41.900 179.000 42.400 ;
        RECT 159.900 34.850 161.200 41.900 ;
        RECT 17.900 31.850 19.600 33.800 ;
        RECT 37.000 31.800 38.950 33.750 ;
        RECT 7.000 29.750 20.000 29.800 ;
        RECT 58.900 29.750 61.400 31.550 ;
        RECT 7.000 28.750 61.400 29.750 ;
        RECT 7.000 28.000 20.000 28.750 ;
        RECT 62.300 23.950 63.200 33.700 ;
        RECT 157.400 33.500 161.550 33.750 ;
        RECT 71.350 32.100 74.500 33.500 ;
        RECT 137.400 32.150 161.550 33.500 ;
        RECT 139.900 29.300 141.900 32.150 ;
        RECT 157.400 30.950 161.550 32.150 ;
        RECT 62.300 23.000 68.350 23.950 ;
        RECT 139.900 23.300 141.900 26.300 ;
        RECT 45.700 21.900 50.650 22.750 ;
        RECT 65.900 17.600 67.950 23.000 ;
        RECT 26.000 17.150 163.450 17.600 ;
        RECT 26.700 16.450 162.700 16.850 ;
        RECT 27.450 12.800 161.950 14.600 ;
        RECT 173.050 5.800 178.950 41.900 ;
      LAYER Metal3 ;
        RECT 7.000 79.350 9.000 82.000 ;
        RECT 57.250 77.000 71.150 80.400 ;
        RECT 68.250 49.350 69.800 77.000 ;
        RECT 73.350 66.350 74.650 69.000 ;
        RECT 72.800 63.900 76.050 66.350 ;
        RECT 61.850 45.400 62.900 46.350 ;
        RECT 4.000 40.000 6.000 42.950 ;
        RECT 62.150 38.300 62.600 45.400 ;
        RECT 64.750 38.250 65.250 46.300 ;
        RECT 68.250 45.250 69.850 49.350 ;
        RECT 73.350 38.000 74.650 63.900 ;
        RECT 159.850 43.700 161.300 43.800 ;
        RECT 143.450 43.650 161.300 43.700 ;
        RECT 143.400 42.400 161.300 43.650 ;
        RECT 143.400 40.250 145.350 42.400 ;
        RECT 159.850 35.350 161.300 42.400 ;
        RECT 17.950 31.850 72.850 33.750 ;
        RECT 159.750 33.350 161.300 35.350 ;
        RECT 7.000 28.000 9.000 29.800 ;
        RECT 45.700 21.900 50.650 31.850 ;
        RECT 139.900 14.250 141.900 24.450 ;
        RECT 159.750 16.450 161.250 33.350 ;
        RECT 139.350 12.850 142.600 14.250 ;
        RECT 173.200 5.900 179.000 11.900 ;
      LAYER Metal4 ;
        RECT 4.000 324.360 14.690 325.350 ;
        RECT 14.990 324.360 21.970 325.350 ;
        RECT 22.270 324.360 29.250 325.350 ;
        RECT 29.550 324.360 36.530 325.350 ;
        RECT 36.830 324.360 43.810 325.350 ;
        RECT 44.110 324.360 51.090 325.350 ;
        RECT 51.390 324.360 58.370 325.350 ;
        RECT 58.670 324.360 65.650 325.350 ;
        RECT 65.950 324.360 72.930 325.350 ;
        RECT 73.230 324.360 80.210 325.350 ;
        RECT 80.510 324.360 87.490 325.350 ;
        RECT 87.790 324.360 94.770 325.350 ;
        RECT 95.070 324.360 102.050 325.350 ;
        RECT 102.350 324.360 109.330 325.350 ;
        RECT 109.630 324.360 116.610 325.350 ;
        RECT 116.910 324.360 123.890 325.350 ;
        RECT 124.190 324.360 131.170 325.350 ;
        RECT 131.470 324.360 138.450 325.350 ;
        RECT 138.750 324.360 145.730 325.350 ;
        RECT 146.030 324.360 153.010 325.350 ;
        RECT 153.310 324.360 160.290 325.350 ;
        RECT 160.590 324.360 167.570 325.350 ;
        RECT 167.870 324.360 174.850 325.350 ;
        RECT 175.150 324.360 182.130 325.350 ;
        RECT 182.430 324.360 182.450 325.350 ;
        RECT 4.000 324.350 182.450 324.360 ;
        RECT 4.000 320.360 6.000 324.350 ;
        RECT 173.200 8.850 179.000 11.900 ;
        RECT 308.000 8.850 310.850 9.000 ;
        RECT 172.950 5.900 310.950 8.850 ;
        RECT 308.000 1.000 310.850 5.900 ;
  END
END tt_um_rahulbhagwat_gf180_bandgap_reference
END LIBRARY

